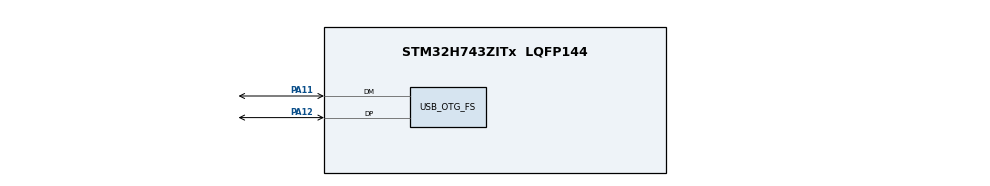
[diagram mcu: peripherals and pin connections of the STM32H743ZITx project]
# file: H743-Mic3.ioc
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PA11.GPIO_Speed=GPIO_SPEED_FREQ_HIGH
Mcu.Family=STM32H7
USB_DEVICE.CLASS_NAME_FS=AUDIO
RCC.CortexFreq_Value=192000000
RCC.SYSCLKSourceVirtual=RCC_SYSCLKSOURCE_PLLCLK
RCC.PLLFRACN=0
PA11.Mode=Device_Only
RCC.SYSCLKSource=RCC_SYSCLKSOURCE_PLLCLK
ProjectManager.StackSize=0x400
USB_DEVICE.PID_AUDIO_FS=0x5731
PA12.Signal=USB_OTG_FS_DP
RCC.HCLKFreq_Value=192000000
RCC.APB2TimFreq_Value=216000000
RCC.AHBFreq_Value=216000000
RCC.HSE_VALUE=8000000
RCC.DIVM1=4
RCC.PLLMUL=RCC_PLL_MUL9
RCC.APB3Freq_Value=96000000
Mcu.Package=LQFP144
RCC.D1PPRE=RCC_APB3_DIV2
NVIC.OTG_FS_IRQn=true\:0\:0\:false\:false\:true\:false\:true
USB_OTG_FS.VirtualMode=Device_Only
RCC.APB2CLKDivider=RCC_HCLK_DIV2
RCC.APB4Freq_Value=96000000
RCC.APB1TimFreq_Value=108000000
PA12.GPIO_Speed=GPIO_SPEED_FREQ_HIGH
USB_DEVICE.USBD_AUDIO_FREQ-AUDIO_FS=48000
RCC.DIVQ1=4
USB_DEVICE.VirtualMode-AUDIO_FS=Audio
USB_DEVICE.VirtualModeFS=Audio_FS
RCC.D2PPRE2=RCC_APB2_DIV2
RCC.D2PPRE1=RCC_APB1_DIV2
RCC.APB1CLKDivider=RCC_HCLK_DIV4
RCC.PWR_Regulator_Voltage_Scale=PWR_REGULATOR_VOLTAGE_SCALE1
ProjectManager.TargetToolchain=STM32CubeIDE
RCC.DIVN1=24
RCC.USBFreq_Value=48000000
RCC.USBCLockSelection=RCC_USBCLKSOURCE_HSI48
board=NUCLEO-H743ZI
RCC.VCOOutputFreq_Value=432000000
RCC.APB2Freq_Value=96000000
RCC.PRESCALERUSB=RCC_USBCLKSOURCE_PLL_DIV1_5
RCC.ADCFreq_Value=129000000
VP_USB_DEVICE_VS_USB_DEVICE_AUDIO_FS.Mode=AUDIO_FS
Mcu.Name=STM32H743ZITx
RCC.48MHZClocksFreq_Value=24000000
RCC.SYSCLKFreq_VALUE=192000000
PA12.Mode=Device_Only
PA11.Signal=USB_OTG_FS_DM
ProjectManager.HeapSize=0x200
RCC.HSI_VALUE=64000000
RCC.PLLQ=9
NVIC.PriorityGroup=NVIC_PRIORITYGROUP_4
RCC.PLLM=25
RCC.PLLN=432
RCC.D3PPRE=RCC_APB4_DIV2
RCC.APB1Freq_Value=96000000

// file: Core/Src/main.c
/* USER CODE BEGIN Header */
/**
  ******************************************************************************
  * @file           : main.c
  * @brief          : Main program body
  ******************************************************************************
  * @attention
  *
  * <h2><center>&copy; Copyright (c) 2021 STMicroelectronics.
  * All rights reserved.</center></h2>
  *
  * This software component is licensed by ST under BSD 3-Clause license,
  * the "License"; You may not use this file except in compliance with the
  * License. You may obtain a copy of the License at:
  *                        opensource.org/licenses/BSD-3-Clause
  *
  ******************************************************************************
  */
/* USER CODE END Header */
#include "main.h"
#include "usb_device.h"

void SystemClock_Config(void);
static void MX_GPIO_Init(void);

int main(void)
{

  /* MCU Configuration--------------------------------------------------------*/

  /* Reset of all peripherals, Initializes the Flash interface and the Systick. */
  HAL_Init();

  /* Configure the system clock */
  SystemClock_Config();

  /* Initialize all configured peripherals */
  MX_GPIO_Init();
  MX_USB_DEVICE_Init();

  /* Infinite loop */
  while (1)
  {

  }
}

void SystemClock_Config(void)
{
  RCC_OscInitTypeDef RCC_OscInitStruct = {0};
  RCC_ClkInitTypeDef RCC_ClkInitStruct = {0};

  /** Supply configuration update enable
  */
  HAL_PWREx_ConfigSupply(PWR_LDO_SUPPLY);
  /** Configure the main internal regulator output voltage
  */
  __HAL_PWR_VOLTAGESCALING_CONFIG(PWR_REGULATOR_VOLTAGE_SCALE3);

  while(!__HAL_PWR_GET_FLAG(PWR_FLAG_VOSRDY)) {}
  /** Initializes the RCC Oscillators according to the specified parameters
  * in the RCC_OscInitTypeDef structure.
  */
  RCC_OscInitStruct.OscillatorType = RCC_OSCILLATORTYPE_HSI48|RCC_OSCILLATORTYPE_HSE;
  RCC_OscInitStruct.HSEState = RCC_HSE_ON;
  RCC_OscInitStruct.HSIState = RCC_HSI_OFF;
//  RCC_OscInitStruct.HSICalibrationValue = RCC_HSICALIBRATION_DEFAULT;
  RCC_OscInitStruct.HSI48State = RCC_HSI48_ON;
  RCC_OscInitStruct.PLL.PLLState = RCC_PLL_ON;
  RCC_OscInitStruct.PLL.PLLSource = RCC_PLLSOURCE_HSE;
  RCC_OscInitStruct.PLL.PLLM = 25;
  RCC_OscInitStruct.PLL.PLLN = 384;
  RCC_OscInitStruct.PLL.PLLP = 2;
  RCC_OscInitStruct.PLL.PLLQ = 13;
  RCC_OscInitStruct.PLL.PLLR = 2;
  RCC_OscInitStruct.PLL.PLLRGE = RCC_PLL1VCIRANGE_0;
  RCC_OscInitStruct.PLL.PLLVCOSEL = RCC_PLL1VCOWIDE;
  RCC_OscInitStruct.PLL.PLLFRACN = 0;
  if (HAL_RCC_OscConfig(&RCC_OscInitStruct) != HAL_OK)
  {
    Error_Handler();
  }
  /** Initializes the CPU, AHB and APB buses clocks
  */
  RCC_ClkInitStruct.ClockType = RCC_CLOCKTYPE_HCLK|RCC_CLOCKTYPE_SYSCLK
                              |RCC_CLOCKTYPE_PCLK1|RCC_CLOCKTYPE_PCLK2
                              |RCC_CLOCKTYPE_D3PCLK1|RCC_CLOCKTYPE_D1PCLK1;
  RCC_ClkInitStruct.SYSCLKSource = RCC_SYSCLKSOURCE_PLLCLK;
  RCC_ClkInitStruct.SYSCLKDivider = RCC_SYSCLK_DIV1;
  RCC_ClkInitStruct.AHBCLKDivider = RCC_HCLK_DIV1;
  RCC_ClkInitStruct.APB3CLKDivider = RCC_APB3_DIV2;
  RCC_ClkInitStruct.APB1CLKDivider = RCC_APB1_DIV2;
  RCC_ClkInitStruct.APB2CLKDivider = RCC_APB2_DIV2;
  RCC_ClkInitStruct.APB4CLKDivider = RCC_APB4_DIV2;

  if (HAL_RCC_ClockConfig(&RCC_ClkInitStruct, FLASH_LATENCY_2) != HAL_OK)
  {
    Error_Handler();
  }
}

static void MX_GPIO_Init(void)
{

  /* GPIO Ports Clock Enable */
  __HAL_RCC_GPIOA_CLK_ENABLE();

}

/* USER CODE BEGIN 4 */
void USBD_error_handler(void)
{
  Error_Handler();
}
/* USER CODE END 4 */

void Error_Handler(void)
{
  __disable_irq();
  while (1)
  {
  }
}

/************************ (C) COPYRIGHT STMicroelectronics *****END OF FILE****/
